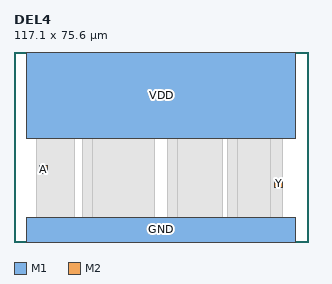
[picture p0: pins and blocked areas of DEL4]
MACRO DEL4
  CLASS CORE ;
  ORIGIN 0 0 ;
  SIZE 117.100 BY 75.600 ;
  SYMMETRY X Y ;
  SITE TR1um_access_site ;
  PIN VDD
    DIRECTION INOUT ;
    USE POWER ;
    PORT
      LAYER M1 ;
        RECT 5.000 41.000 112.100 75.600 ;
    END
  END VDD
  PIN GND
    DIRECTION INOUT ;
    USE GROUND ;
    PORT
      LAYER M1 ;
        RECT 5.000 0.000 112.100 9.800 ;
    END
  END GND
  PIN A
    DIRECTION INPUT ;
    USE SIGNAL ;
    PORT
      LAYER M2 ;
        RECT 10.100 27.100 13.500 30.500 ;
    END
  END A
  PIN Y
    DIRECTION OUTPUT ;
    USE SIGNAL ;
    PORT
      LAYER M2 ;
        RECT 103.600 21.600 107.000 25.000 ;
    END
  END Y
  OBS
    LAYER M1 ;
      RECT 10.100 22.000 14.500 30.500 ;
    LAYER M1 ;
      RECT 9.100 6.400 24.000 51.200 ;
    LAYER M1 ;
      RECT 27.100 6.400 39.900 51.200 ;
    LAYER M1 ;
      RECT 31.100 6.400 55.900 51.200 ;
    LAYER M1 ;
      RECT 61.100 6.400 73.000 51.200 ;
    LAYER M1 ;
      RECT 65.100 6.400 82.900 51.200 ;
    LAYER M1 ;
      RECT 85.100 6.400 95.900 51.200 ;
    LAYER M1 ;
      RECT 89.100 6.400 101.900 51.200 ;
    LAYER M1 ;
      RECT 102.100 6.400 107.000 51.200 ;
    LAYER V1 ;
      RECT 104.600 22.600 106.000 24.000 ;
    LAYER V1 ;
      RECT 11.100 28.100 12.500 29.500 ;
  END
END DEL4
